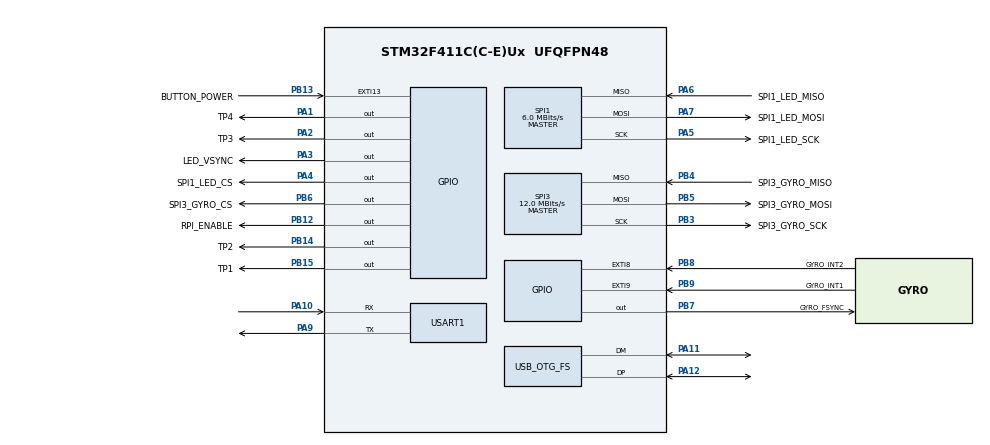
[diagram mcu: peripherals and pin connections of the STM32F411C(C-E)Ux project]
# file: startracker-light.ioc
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Dma.Request0=SPI1_TX
Dma.Request1=SPI1_RX
Dma.Request2=SPI3_RX
Dma.Request3=SPI3_TX
Dma.SPI1_RX.1.Direction=DMA_PERIPH_TO_MEMORY
Dma.SPI1_RX.1.FIFOMode=DMA_FIFOMODE_DISABLE
Dma.SPI1_RX.1.Instance=DMA2_Stream0
Dma.SPI1_RX.1.MemDataAlignment=DMA_MDATAALIGN_BYTE
Dma.SPI1_RX.1.MemInc=DMA_MINC_ENABLE
Dma.SPI1_RX.1.Mode=DMA_NORMAL
Dma.SPI1_RX.1.PeriphDataAlignment=DMA_PDATAALIGN_BYTE
Dma.SPI1_RX.1.PeriphInc=DMA_PINC_DISABLE
Dma.SPI1_RX.1.Priority=DMA_PRIORITY_LOW
Dma.SPI1_TX.0.Direction=DMA_MEMORY_TO_PERIPH
Dma.SPI1_TX.0.FIFOMode=DMA_FIFOMODE_DISABLE
Dma.SPI1_TX.0.Instance=DMA2_Stream2
Dma.SPI1_TX.0.MemDataAlignment=DMA_MDATAALIGN_BYTE
Dma.SPI1_TX.0.MemInc=DMA_MINC_ENABLE
Dma.SPI1_TX.0.Mode=DMA_NORMAL
Dma.SPI1_TX.0.PeriphDataAlignment=DMA_PDATAALIGN_BYTE
Dma.SPI1_TX.0.PeriphInc=DMA_PINC_DISABLE
Dma.SPI1_TX.0.Priority=DMA_PRIORITY_LOW
Dma.SPI3_RX.2.Direction=DMA_PERIPH_TO_MEMORY
Dma.SPI3_RX.2.FIFOMode=DMA_FIFOMODE_DISABLE
Dma.SPI3_RX.2.Instance=DMA1_Stream0
Dma.SPI3_RX.2.MemDataAlignment=DMA_MDATAALIGN_BYTE
Dma.SPI3_RX.2.MemInc=DMA_MINC_ENABLE
Dma.SPI3_RX.2.Mode=DMA_NORMAL
Dma.SPI3_RX.2.PeriphDataAlignment=DMA_PDATAALIGN_BYTE
Dma.SPI3_RX.2.PeriphInc=DMA_PINC_DISABLE
Dma.SPI3_RX.2.Priority=DMA_PRIORITY_LOW
Dma.SPI3_TX.3.Direction=DMA_MEMORY_TO_PERIPH
Dma.SPI3_TX.3.FIFOMode=DMA_FIFOMODE_DISABLE
Dma.SPI3_TX.3.Instance=DMA1_Stream5
Dma.SPI3_TX.3.MemDataAlignment=DMA_MDATAALIGN_BYTE
Dma.SPI3_TX.3.MemInc=DMA_MINC_ENABLE
Dma.SPI3_TX.3.Mode=DMA_NORMAL
Dma.SPI3_TX.3.PeriphDataAlignment=DMA_PDATAALIGN_BYTE
Dma.SPI3_TX.3.PeriphInc=DMA_PINC_DISABLE
Dma.SPI3_TX.3.Priority=DMA_PRIORITY_LOW
Mcu.Family=STM32F4
Mcu.Name=STM32F411C(C-E)Ux
Mcu.Package=UFQFPN48
NVIC.DMA1_Stream0_IRQn=true\:0\:0\:false\:false\:true\:false\:true\:true
NVIC.DMA1_Stream5_IRQn=true\:0\:0\:false\:false\:true\:false\:true\:true
NVIC.DMA2_Stream0_IRQn=true\:0\:0\:false\:false\:true\:false\:true\:true
NVIC.DMA2_Stream2_IRQn=true\:0\:0\:false\:false\:true\:false\:true\:true
NVIC.EXTI15_10_IRQn=true\:0\:0\:false\:false\:true\:true\:true\:true
NVIC.EXTI9_5_IRQn=true\:0\:0\:false\:false\:true\:true\:true\:true
NVIC.OTG_FS_IRQn=true\:0\:0\:false\:false\:true\:false\:true\:true
NVIC.PriorityGroup=NVIC_PRIORITYGROUP_4
NVIC.USART1_IRQn=true\:0\:0\:false\:false\:true\:true\:true\:true
PA1.GPIO_Label=TP4
PA1.Signal=GPIO_Output
PA10.Mode=Asynchronous
PA10.Signal=USART1_RX
PA11.Mode=Device_Only
PA11.Signal=USB_OTG_FS_DM
PA12.Mode=Device_Only
PA12.Signal=USB_OTG_FS_DP
PA13.Mode=Serial_Wire
PA13.Signal=SYS_JTMS-SWDIO
PA14.Mode=Serial_Wire
PA14.Signal=SYS_JTCK-SWCLK
PA2.GPIO_Label=TP3
PA2.Signal=GPIO_Output
PA3.GPIO_Label=LED_VSYNC
PA3.Signal=GPIO_Output
PA4.GPIO_Label=SPI1_LED_CS
PA4.Signal=GPIO_Output
PA5.GPIO_Label=SPI1_LED_SCK
PA5.Mode=Full_Duplex_Master
PA5.Signal=SPI1_SCK
PA6.GPIO_Label=SPI1_LED_MISO
PA6.Mode=Full_Duplex_Master
PA6.Signal=SPI1_MISO
PA7.GPIO_Label=SPI1_LED_MOSI
PA7.Mode=Full_Duplex_Master
PA7.Signal=SPI1_MOSI
PA9.Mode=Asynchronous
PA9.Signal=USART1_TX
PB12.GPIO_Label=RPI_ENABLE
PB12.Signal=GPIO_Output
PB13.GPIO_Label=BUTTON_POWER
PB13.Signal=GPXTI13
PB14.GPIO_Label=TP2
PB14.Signal=GPIO_Output
PB15.GPIO_Label=TP1
PB15.Signal=GPIO_Output
PB3.GPIO_Label=SPI3_GYRO_SCK
PB3.Mode=Full_Duplex_Master
PB3.Signal=SPI3_SCK
PB4.GPIO_Label=SPI3_GYRO_MISO
PB4.Mode=Full_Duplex_Master
PB4.Signal=SPI3_MISO
PB5.GPIO_Label=SPI3_GYRO_MOSI
PB5.Mode=Full_Duplex_Master
PB5.Signal=SPI3_MOSI
PB6.GPIO_Label=SPI3_GYRO_CS
PB6.Signal=GPIO_Output
PB7.GPIO_Label=GYRO_FSYNC
PB7.Signal=GPIO_Output
PB8.GPIO_Label=GYRO_INT2
PB8.Signal=GPXTI8
PB9.GPIO_Label=GYRO_INT1
PB9.Signal=GPXTI9
PH0\ -\ OSC_IN.Mode=HSE-External-Oscillator
PH0\ -\ OSC_IN.Signal=RCC_OSC_IN
PH1\ -\ OSC_OUT.Mode=HSE-External-Oscillator
PH1\ -\ OSC_OUT.Signal=RCC_OSC_OUT
ProjectManager.HeapSize=0x200
ProjectManager.StackSize=0x400
ProjectManager.TargetToolchain=STM32CubeIDE
RCC.48MHZClocksFreq_Value=48000000
RCC.AHBFreq_Value=96000000
RCC.APB1CLKDivider=RCC_HCLK_DIV2
RCC.APB1Freq_Value=48000000
RCC.APB1TimFreq_Value=96000000
RCC.APB2Freq_Value=96000000
RCC.APB2TimFreq_Value=96000000
RCC.CortexFreq_Value=96000000
RCC.HCLKFreq_Value=96000000
RCC.HSE_VALUE=25000000
RCC.HSI_VALUE=16000000
RCC.LSE_VALUE=32768
RCC.PLLM=25
RCC.SYSCLKFreq_VALUE=96000000
RCC.SYSCLKSource=RCC_SYSCLKSOURCE_PLLCLK
RCC.VCOOutputFreq_Value=192000000
SPI1.BaudRatePrescaler=SPI_BAUDRATEPRESCALER_16
SPI1.CalculateBaudRate=6.0 MBits/s
SPI1.Direction=SPI_DIRECTION_2LINES
SPI1.Mode=SPI_MODE_MASTER
SPI1.VirtualType=VM_MASTER
SPI3.BaudRatePrescaler=SPI_BAUDRATEPRESCALER_4
SPI3.CalculateBaudRate=12.0 MBits/s
SPI3.Direction=SPI_DIRECTION_2LINES
SPI3.Mode=SPI_MODE_MASTER
SPI3.VirtualType=VM_MASTER
USART1.VirtualMode=VM_ASYNC
USB_DEVICE.CLASS_NAME_FS=CDC
USB_DEVICE.VirtualMode=Cdc
USB_DEVICE.VirtualModeFS=Cdc_FS
USB_OTG_FS.VirtualMode=Device_Only
VP_USB_DEVICE_VS_USB_DEVICE_CDC_FS.Mode=CDC_FS
board=custom

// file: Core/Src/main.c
/* USER CODE BEGIN Header */
/**
  ******************************************************************************
  * @file           : main.c
  * @brief          : Main program body
  ******************************************************************************
  * @attention
  *
  * Copyright (c) 2025 STMicroelectronics.
  * All rights reserved.
  *
  * This software is licensed under terms that can be found in the LICENSE file
  * in the root directory of this software component.
  * If no LICENSE file comes with this software, it is provided AS-IS.
  *
  ******************************************************************************
  */
/* USER CODE END Header */
#include "main.h"

/* USER CODE BEGIN Includes */
#include "application.h"
/* USER CODE END Includes */

SPI_HandleTypeDef hspi1;
SPI_HandleTypeDef hspi3;
DMA_HandleTypeDef hdma_spi1_tx;
DMA_HandleTypeDef hdma_spi1_rx;
DMA_HandleTypeDef hdma_spi3_rx;
DMA_HandleTypeDef hdma_spi3_tx;

UART_HandleTypeDef huart1;
DMA_HandleTypeDef hdma_usart1_rx;
DMA_HandleTypeDef hdma_usart1_tx;

void SystemClock_Config(void);
static void MX_GPIO_Init(void);
static void MX_DMA_Init(void);
static void MX_SPI1_Init(void);
static void MX_SPI3_Init(void);
static void MX_USART1_UART_Init(void);

int main(void)
{

  /* MCU Configuration--------------------------------------------------------*/

  /* Reset of all peripherals, Initializes the Flash interface and the Systick. */
  HAL_Init();

  /* Configure the system clock */
  SystemClock_Config();

  /* Initialize all configured peripherals */
  MX_GPIO_Init();
  MX_DMA_Init();
  MX_SPI1_Init();
  MX_SPI3_Init();
  MX_USART1_UART_Init();

  /* Infinite loop */
  /* USER CODE BEGIN WHILE */
  app_init(&hspi1, &hspi3, &huart1);
  while (1)
  {
    /* USER CODE END WHILE */

  }
}

void SystemClock_Config(void)
{
  RCC_OscInitTypeDef RCC_OscInitStruct = {0};
  RCC_ClkInitTypeDef RCC_ClkInitStruct = {0};

  /** Configure the main internal regulator output voltage
  */
  __HAL_RCC_PWR_CLK_ENABLE();
  __HAL_PWR_VOLTAGESCALING_CONFIG(PWR_REGULATOR_VOLTAGE_SCALE1);

  /** Initializes the RCC Oscillators according to the specified parameters
  * in the RCC_OscInitTypeDef structure.
  */
  RCC_OscInitStruct.OscillatorType = RCC_OSCILLATORTYPE_HSE;
  RCC_OscInitStruct.HSEState = RCC_HSE_ON;
  RCC_OscInitStruct.PLL.PLLState = RCC_PLL_ON;
  RCC_OscInitStruct.PLL.PLLSource = RCC_PLLSOURCE_HSE;
  RCC_OscInitStruct.PLL.PLLM = 16;
  RCC_OscInitStruct.PLL.PLLN = 192;
  RCC_OscInitStruct.PLL.PLLP = RCC_PLLP_DIV2;
  RCC_OscInitStruct.PLL.PLLQ = 4;
  if (HAL_RCC_OscConfig(&RCC_OscInitStruct) != HAL_OK)
  {
    Error_Handler();
  }

  /** Initializes the CPU, AHB and APB buses clocks
  */
  RCC_ClkInitStruct.ClockType = RCC_CLOCKTYPE_HCLK|RCC_CLOCKTYPE_SYSCLK
                              |RCC_CLOCKTYPE_PCLK1|RCC_CLOCKTYPE_PCLK2;
  RCC_ClkInitStruct.SYSCLKSource = RCC_SYSCLKSOURCE_PLLCLK;
  RCC_ClkInitStruct.AHBCLKDivider = RCC_SYSCLK_DIV1;
  RCC_ClkInitStruct.APB1CLKDivider = RCC_HCLK_DIV2;
  RCC_ClkInitStruct.APB2CLKDivider = RCC_HCLK_DIV1;

  if (HAL_RCC_ClockConfig(&RCC_ClkInitStruct, FLASH_LATENCY_3) != HAL_OK)
  {
    Error_Handler();
  }
}

static void MX_SPI1_Init(void)
{

  /* SPI1 parameter configuration*/
  hspi1.Instance = SPI1;
  hspi1.Init.Mode = SPI_MODE_MASTER;
  hspi1.Init.Direction = SPI_DIRECTION_2LINES;
  hspi1.Init.DataSize = SPI_DATASIZE_8BIT;
  hspi1.Init.CLKPolarity = SPI_POLARITY_LOW;
  hspi1.Init.CLKPhase = SPI_PHASE_1EDGE;
  hspi1.Init.NSS = SPI_NSS_SOFT;
  hspi1.Init.BaudRatePrescaler = SPI_BAUDRATEPRESCALER_8;
  hspi1.Init.FirstBit = SPI_FIRSTBIT_MSB;
  hspi1.Init.TIMode = SPI_TIMODE_DISABLE;
  hspi1.Init.CRCCalculation = SPI_CRCCALCULATION_DISABLE;
  hspi1.Init.CRCPolynomial = 10;
  if (HAL_SPI_Init(&hspi1) != HAL_OK)
  {
    Error_Handler();
  }

}

static void MX_SPI3_Init(void)
{

  /* SPI3 parameter configuration*/
  hspi3.Instance = SPI3;
  hspi3.Init.Mode = SPI_MODE_MASTER;
  hspi3.Init.Direction = SPI_DIRECTION_2LINES;
  hspi3.Init.DataSize = SPI_DATASIZE_8BIT;
  hspi3.Init.CLKPolarity = SPI_POLARITY_LOW;
  hspi3.Init.CLKPhase = SPI_PHASE_1EDGE;
  hspi3.Init.NSS = SPI_NSS_SOFT;
  hspi3.Init.BaudRatePrescaler = SPI_BAUDRATEPRESCALER_2;
  hspi3.Init.FirstBit = SPI_FIRSTBIT_MSB;
  hspi3.Init.TIMode = SPI_TIMODE_DISABLE;
  hspi3.Init.CRCCalculation = SPI_CRCCALCULATION_DISABLE;
  hspi3.Init.CRCPolynomial = 10;
  if (HAL_SPI_Init(&hspi3) != HAL_OK)
  {
    Error_Handler();
  }

}

static void MX_USART1_UART_Init(void)
{

  huart1.Instance = USART1;
  huart1.Init.BaudRate = 1000000;
  huart1.Init.WordLength = UART_WORDLENGTH_8B;
  huart1.Init.StopBits = UART_STOPBITS_1;
  huart1.Init.Parity = UART_PARITY_NONE;
  huart1.Init.Mode = UART_MODE_TX_RX;
  huart1.Init.HwFlowCtl = UART_HWCONTROL_NONE;
  huart1.Init.OverSampling = UART_OVERSAMPLING_16;
  if (HAL_UART_Init(&huart1) != HAL_OK)
  {
    Error_Handler();
  }

}

static void MX_DMA_Init(void)
{

  /* DMA controller clock enable */
  __HAL_RCC_DMA2_CLK_ENABLE();
  __HAL_RCC_DMA1_CLK_ENABLE();

  /* DMA interrupt init */
  /* DMA1_Stream0_IRQn interrupt configuration */
  HAL_NVIC_SetPriority(DMA1_Stream0_IRQn, 0, 0);
  HAL_NVIC_EnableIRQ(DMA1_Stream0_IRQn);
  /* DMA1_Stream5_IRQn interrupt configuration */
  HAL_NVIC_SetPriority(DMA1_Stream5_IRQn, 0, 0);
  HAL_NVIC_EnableIRQ(DMA1_Stream5_IRQn);
  /* DMA2_Stream0_IRQn interrupt configuration */
  HAL_NVIC_SetPriority(DMA2_Stream0_IRQn, 0, 0);
  HAL_NVIC_EnableIRQ(DMA2_Stream0_IRQn);
  /* DMA2_Stream2_IRQn interrupt configuration */
  HAL_NVIC_SetPriority(DMA2_Stream2_IRQn, 0, 0);
  HAL_NVIC_EnableIRQ(DMA2_Stream2_IRQn);
  /* DMA2_Stream5_IRQn interrupt configuration */
  HAL_NVIC_SetPriority(DMA2_Stream5_IRQn, 0, 0);
  HAL_NVIC_EnableIRQ(DMA2_Stream5_IRQn);
  /* DMA2_Stream7_IRQn interrupt configuration */
  HAL_NVIC_SetPriority(DMA2_Stream7_IRQn, 0, 0);
  HAL_NVIC_EnableIRQ(DMA2_Stream7_IRQn);

}

static void MX_GPIO_Init(void)
{
  GPIO_InitTypeDef GPIO_InitStruct = {0};

  /* GPIO Ports Clock Enable */
  __HAL_RCC_GPIOH_CLK_ENABLE();
  __HAL_RCC_GPIOA_CLK_ENABLE();
  __HAL_RCC_GPIOB_CLK_ENABLE();

  /*Configure GPIO pin Output Level */
  HAL_GPIO_WritePin(GPIOA, TP4_Pin|TP3_Pin|LED_VSYNC_Pin|SPI1_LED_CS_Pin, GPIO_PIN_RESET);

  /*Configure GPIO pin Output Level */
  HAL_GPIO_WritePin(GPIOB, RPI_ENABLE_Pin|TP2_Pin|TP1_Pin|SPI3_GYRO_CS_Pin
                          |GYRO_FSYNC_Pin, GPIO_PIN_RESET);

  /*Configure GPIO pins : TP4_Pin TP3_Pin LED_VSYNC_Pin SPI1_LED_CS_Pin */
  GPIO_InitStruct.Pin = TP4_Pin|TP3_Pin|LED_VSYNC_Pin|SPI1_LED_CS_Pin;
  GPIO_InitStruct.Mode = GPIO_MODE_OUTPUT_PP;
  GPIO_InitStruct.Pull = GPIO_NOPULL;
  GPIO_InitStruct.Speed = GPIO_SPEED_FREQ_LOW;
  HAL_GPIO_Init(GPIOA, &GPIO_InitStruct);

  /*Configure GPIO pins : RPI_ENABLE_Pin TP2_Pin TP1_Pin SPI3_GYRO_CS_Pin
                           GYRO_FSYNC_Pin */
  GPIO_InitStruct.Pin = RPI_ENABLE_Pin|TP2_Pin|TP1_Pin|SPI3_GYRO_CS_Pin
                          |GYRO_FSYNC_Pin;
  GPIO_InitStruct.Mode = GPIO_MODE_OUTPUT_PP;
  GPIO_InitStruct.Pull = GPIO_NOPULL;
  GPIO_InitStruct.Speed = GPIO_SPEED_FREQ_LOW;
  HAL_GPIO_Init(GPIOB, &GPIO_InitStruct);

  /*Configure GPIO pins : BUTTON_POWER_Pin GYRO_INT2_Pin GYRO_INT1_Pin */
  GPIO_InitStruct.Pin = BUTTON_POWER_Pin|GYRO_INT2_Pin|GYRO_INT1_Pin;
  GPIO_InitStruct.Mode = GPIO_MODE_IT_RISING;
  GPIO_InitStruct.Pull = GPIO_NOPULL;
  HAL_GPIO_Init(GPIOB, &GPIO_InitStruct);

  /* EXTI interrupt init*/
  HAL_NVIC_SetPriority(EXTI9_5_IRQn, 0, 0);
  HAL_NVIC_EnableIRQ(EXTI9_5_IRQn);

  HAL_NVIC_SetPriority(EXTI15_10_IRQn, 0, 0);
  HAL_NVIC_EnableIRQ(EXTI15_10_IRQn);

}

void Error_Handler(void)
{
  __disable_irq();
  while (1)
  {
  }
}
